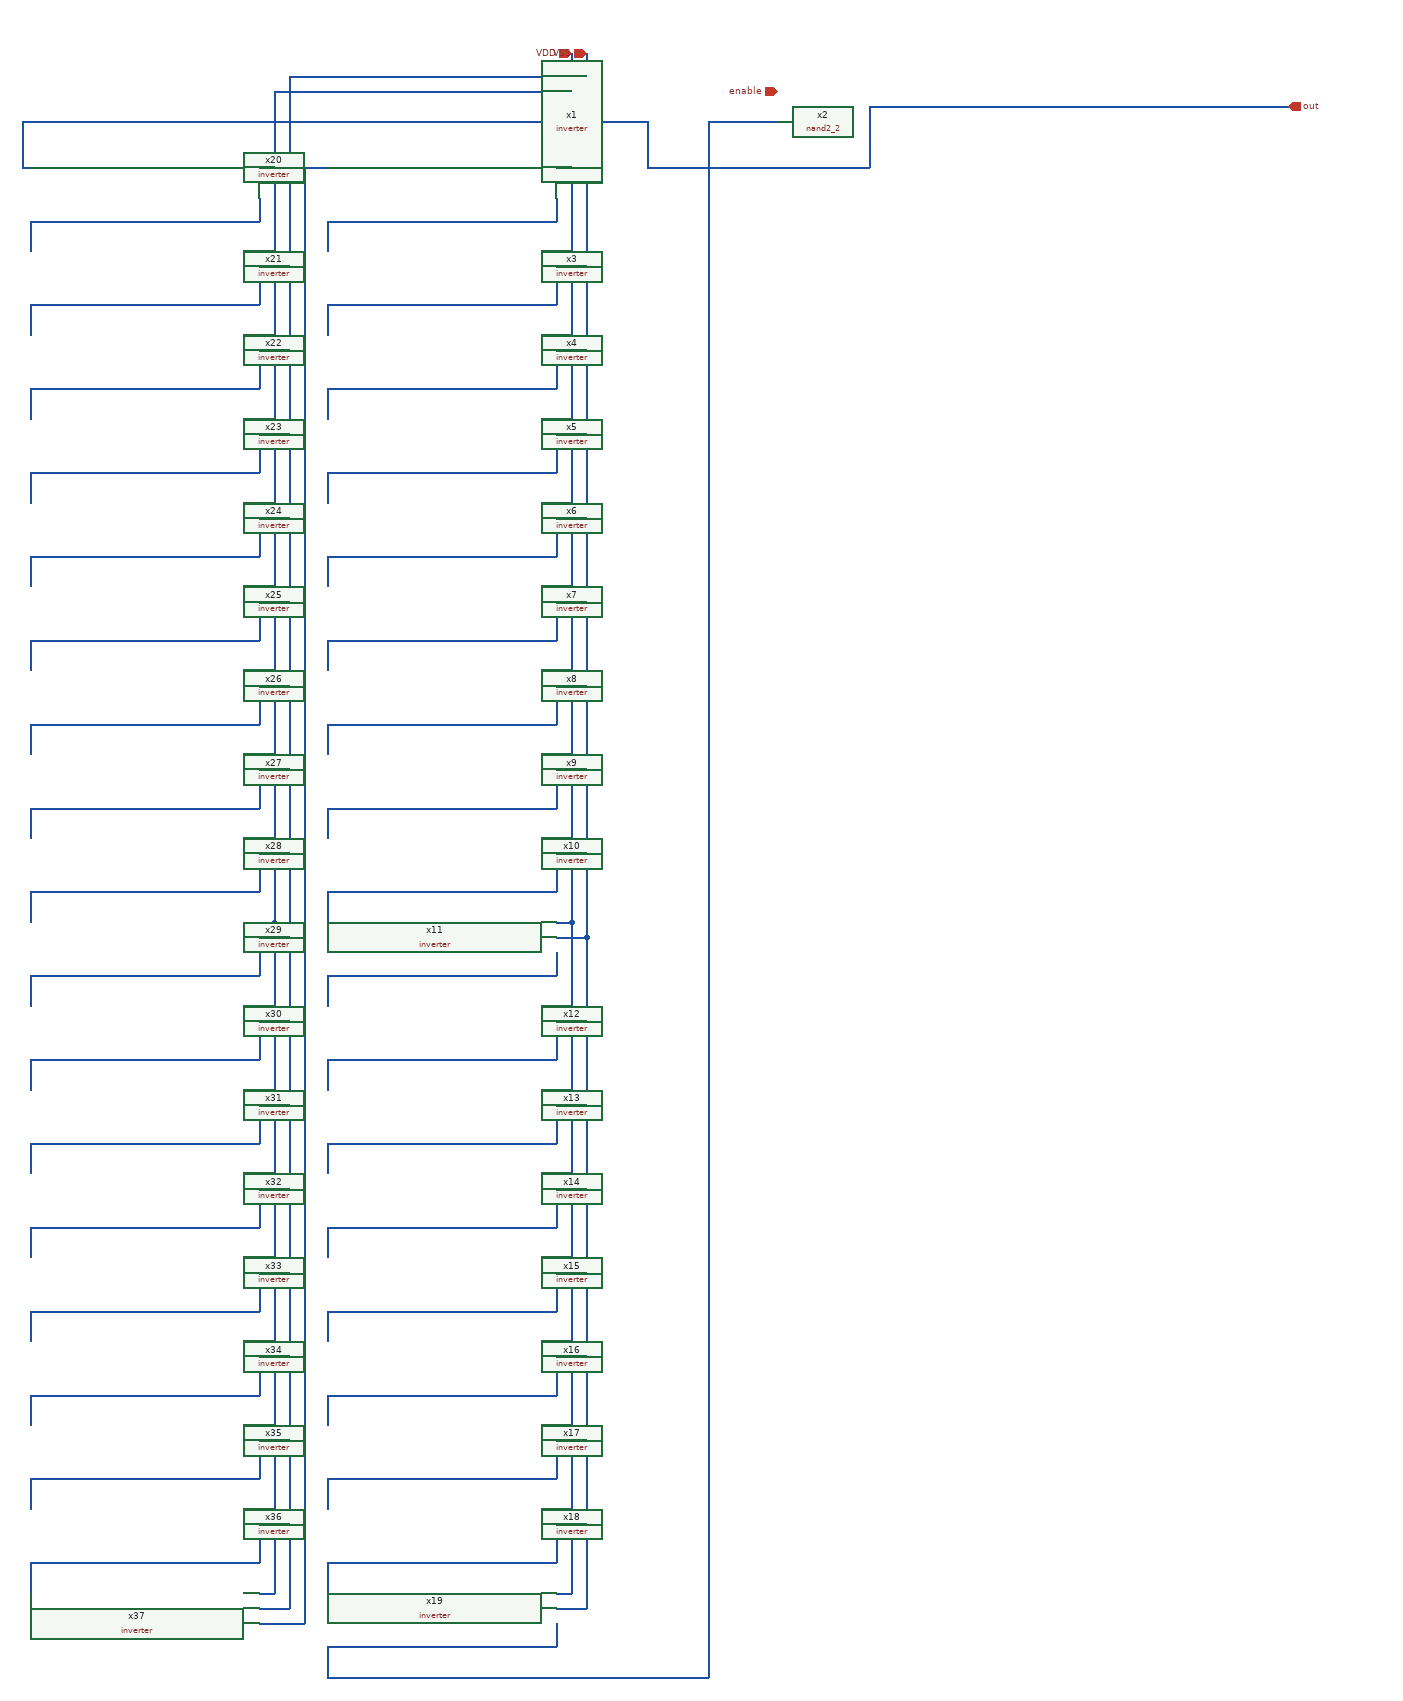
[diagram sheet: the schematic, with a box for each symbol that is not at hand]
v {xschem version=3.4.5 file_version=1.2
}
G {}
K {}
V {}
S {}
E {}
N -80 120 210 120 {
lab=pre_drive}
N -200 120 -180 120 {
lab=VDD}
N -200 140 -160 140 {
lab=VSS}
N -200 160 -200 190 {
lab=#net2}
N -500 190 -200 190 {
lab=#net2}
N -500 190 -500 230 {
lab=#net2}
N -200 230 -180 230 {
lab=VDD}
N -200 250 -160 250 {
lab=VSS}
N -200 270 -200 300 {
lab=#net3}
N -500 300 -200 300 {
lab=#net3}
N -500 300 -500 340 {
lab=#net3}
N -200 340 -180 340 {
lab=VDD}
N -200 360 -160 360 {
lab=VSS}
N -200 380 -200 410 {
lab=#net4}
N -500 410 -200 410 {
lab=#net4}
N -500 410 -500 450 {
lab=#net4}
N -200 450 -180 450 {
lab=VDD}
N -200 470 -160 470 {
lab=VSS}
N -200 490 -200 520 {
lab=#net5}
N -500 520 -200 520 {
lab=#net5}
N -500 520 -500 560 {
lab=#net5}
N -200 560 -180 560 {
lab=VDD}
N -200 580 -160 580 {
lab=VSS}
N -200 600 -200 630 {
lab=#net6}
N -500 630 -200 630 {
lab=#net6}
N -500 630 -500 670 {
lab=#net6}
N -200 670 -180 670 {
lab=VDD}
N -200 690 -160 690 {
lab=VSS}
N -200 710 -200 740 {
lab=#net7}
N -500 740 -200 740 {
lab=#net7}
N -500 740 -500 780 {
lab=#net7}
N -200 780 -180 780 {
lab=VDD}
N -200 800 -160 800 {
lab=VSS}
N -200 820 -200 850 {
lab=#net8}
N -500 850 -200 850 {
lab=#net8}
N -500 850 -500 890 {
lab=#net8}
N -200 890 -180 890 {
lab=VDD}
N -200 910 -160 910 {
lab=VSS}
N -200 930 -200 960 {
lab=#net9}
N -500 960 -200 960 {
lab=#net9}
N -500 960 -500 1000 {
lab=#net9}
N -200 1000 -180 1000 {
lab=VDD}
N -200 1020 -160 1020 {
lab=VSS}
N -200 1040 -200 1070 {
lab=#net10}
N -500 1070 -200 1070 {
lab=#net10}
N -500 1070 -500 1110 {
lab=#net10}
N -200 1110 -180 1110 {
lab=VDD}
N -200 1130 -160 1130 {
lab=VSS}
N -200 1150 -200 1180 {
lab=#net11}
N -500 1180 -200 1180 {
lab=#net11}
N -500 1180 -500 1220 {
lab=#net11}
N -160 -30 -160 1130 {
lab=VSS}
N -180 -30 -180 1110 {
lab=VDD}
N -200 1220 -180 1220 {
lab=VDD}
N -200 1240 -160 1240 {
lab=VSS}
N -200 1260 -200 1290 {
lab=#net12}
N -500 1290 -200 1290 {
lab=#net12}
N -500 1290 -500 1330 {
lab=#net12}
N -200 1330 -180 1330 {
lab=VDD}
N -200 1350 -160 1350 {
lab=VSS}
N -200 1370 -200 1400 {
lab=#net13}
N -500 1400 -200 1400 {
lab=#net13}
N -500 1400 -500 1440 {
lab=#net13}
N -200 1440 -180 1440 {
lab=VDD}
N -200 1460 -160 1460 {
lab=VSS}
N -200 1480 -200 1510 {
lab=#net14}
N -500 1510 -200 1510 {
lab=#net14}
N -500 1510 -500 1550 {
lab=#net14}
N -200 1550 -180 1550 {
lab=VDD}
N -200 1570 -160 1570 {
lab=VSS}
N -200 1590 -200 1620 {
lab=#net15}
N -500 1620 -200 1620 {
lab=#net15}
N -500 1620 -500 1660 {
lab=#net15}
N -200 1660 -180 1660 {
lab=VDD}
N -200 1680 -160 1680 {
lab=VSS}
N -200 1700 -200 1730 {
lab=#net16}
N -500 1730 -200 1730 {
lab=#net16}
N -500 1730 -500 1770 {
lab=#net16}
N -200 1770 -180 1770 {
lab=VDD}
N -200 1790 -160 1790 {
lab=VSS}
N -200 1810 -200 1840 {
lab=#net17}
N -500 1840 -200 1840 {
lab=#net17}
N -500 1840 -500 1880 {
lab=#net17}
N -200 1880 -180 1880 {
lab=VDD}
N -200 1900 -160 1900 {
lab=VSS}
N -200 1920 -200 1950 {
lab=#net18}
N -500 1950 -200 1950 {
lab=#net18}
N -500 1950 -500 1990 {
lab=#net18}
N -200 1990 -180 1990 {
lab=VDD}
N -200 2010 -160 2010 {
lab=VSS}
N -200 2030 -200 2060 {
lab=#net19}
N -500 2060 -200 2060 {
lab=#net19}
N -500 2060 -500 2100 {
lab=#net19}
N -180 1110 -180 1990 {
lab=VDD}
N -160 1130 -160 2010 {
lab=VSS}
N -500 2100 -0 2100 {
lab=#net19}
N 0 60 0 2100 {
lab=#net19}
N 0 60 90 60 {
lab=#net19}
N -80 60 -80 120 {
lab=pre_drive}
N -500 60 -80 60 {
lab=pre_drive}
N 660 40 760 40 {
lab=out}
N 210 40 210 120 {}
N 210 40 660 40 {}
N -590 120 -570 120 {
lab=VDD}
N -590 140 -550 140 {
lab=VSS}
N -590 160 -590 190 {
lab=#net2}
N -890 190 -590 190 {
lab=#net2}
N -890 190 -890 230 {
lab=#net2}
N -590 230 -570 230 {
lab=VDD}
N -590 250 -550 250 {
lab=VSS}
N -590 270 -590 300 {
lab=#net3}
N -890 300 -590 300 {
lab=#net3}
N -890 300 -890 340 {
lab=#net3}
N -590 340 -570 340 {
lab=VDD}
N -590 360 -550 360 {
lab=VSS}
N -590 380 -590 410 {
lab=#net4}
N -890 410 -590 410 {
lab=#net4}
N -890 410 -890 450 {
lab=#net4}
N -590 450 -570 450 {
lab=VDD}
N -590 470 -550 470 {
lab=VSS}
N -590 490 -590 520 {
lab=#net5}
N -890 520 -590 520 {
lab=#net5}
N -890 520 -890 560 {
lab=#net5}
N -590 560 -570 560 {
lab=VDD}
N -590 580 -550 580 {
lab=VSS}
N -590 600 -590 630 {
lab=#net6}
N -890 630 -590 630 {
lab=#net6}
N -890 630 -890 670 {
lab=#net6}
N -590 670 -570 670 {
lab=VDD}
N -590 690 -550 690 {
lab=VSS}
N -590 710 -590 740 {
lab=#net7}
N -890 740 -590 740 {
lab=#net7}
N -890 740 -890 780 {
lab=#net7}
N -590 780 -570 780 {
lab=VDD}
N -590 800 -550 800 {
lab=VSS}
N -590 820 -590 850 {
lab=#net8}
N -890 850 -590 850 {
lab=#net8}
N -890 850 -890 890 {
lab=#net8}
N -590 890 -570 890 {
lab=VDD}
N -590 910 -550 910 {
lab=VSS}
N -590 930 -590 960 {
lab=#net9}
N -890 960 -590 960 {
lab=#net9}
N -890 960 -890 1000 {
lab=#net9}
N -590 1000 -570 1000 {
lab=VDD}
N -590 1020 -550 1020 {
lab=VSS}
N -590 1040 -590 1070 {
lab=#net10}
N -890 1070 -590 1070 {
lab=#net10}
N -890 1070 -890 1110 {
lab=#net10}
N -590 1110 -570 1110 {
lab=VDD}
N -590 1130 -550 1130 {
lab=VSS}
N -590 1150 -590 1180 {
lab=#net11}
N -890 1180 -590 1180 {
lab=#net11}
N -890 1180 -890 1220 {
lab=#net11}
N -590 1220 -570 1220 {
lab=VDD}
N -590 1240 -550 1240 {
lab=VSS}
N -590 1260 -590 1290 {
lab=#net12}
N -890 1290 -590 1290 {
lab=#net12}
N -890 1290 -890 1330 {
lab=#net12}
N -590 1330 -570 1330 {
lab=VDD}
N -590 1350 -550 1350 {
lab=VSS}
N -590 1370 -590 1400 {
lab=#net13}
N -890 1400 -590 1400 {
lab=#net13}
N -890 1400 -890 1440 {
lab=#net13}
N -590 1440 -570 1440 {
lab=VDD}
N -590 1460 -550 1460 {
lab=VSS}
N -590 1480 -590 1510 {
lab=#net14}
N -890 1510 -590 1510 {
lab=#net14}
N -890 1510 -890 1550 {
lab=#net14}
N -590 1550 -570 1550 {
lab=VDD}
N -590 1570 -550 1570 {
lab=VSS}
N -590 1590 -590 1620 {
lab=#net15}
N -890 1620 -590 1620 {
lab=#net15}
N -890 1620 -890 1660 {
lab=#net15}
N -590 1660 -570 1660 {
lab=VDD}
N -590 1680 -550 1680 {
lab=VSS}
N -590 1700 -590 1730 {
lab=#net16}
N -890 1730 -590 1730 {
lab=#net16}
N -890 1730 -890 1770 {
lab=#net16}
N -590 1770 -570 1770 {
lab=VDD}
N -590 1790 -550 1790 {
lab=VSS}
N -590 1810 -590 1840 {
lab=#net17}
N -890 1840 -590 1840 {
lab=#net17}
N -890 1840 -890 1880 {
lab=#net17}
N -590 1880 -570 1880 {
lab=VDD}
N -590 1900 -550 1900 {
lab=VSS}
N -590 1920 -590 1950 {
lab=#net18}
N -890 1950 -590 1950 {
lab=#net18}
N -890 1950 -890 1990 {
lab=#net18}
N -590 1990 -570 1990 {
lab=VDD}
N -570 1110 -570 1990 {
lab=VDD}
N -590 2010 -550 2010 {}
N -550 0 -550 2010 {}
N -550 0 -160 0 {}
N -570 20 -180 20 {}
N -570 20 -570 1110 {}
N -900 60 -500 60 {}
N -900 60 -900 120 {}
N -900 120 -890 120 {}
N -590 2030 -530 2030 {}
N -530 120 -530 2030 {}
N -530 120 -500 120 {}
C {devices/iopin.sym} -180 -30 2 0 {name=p1 lab=VDD
}
C {devices/ipin.sym} 90 20 0 0 {name=p3 lab=enable}
C {sky130_stdcells/nand2_2.sym} 150 40 0 0 {name=x2 VGND=VSS VNB=VSS VPB=VDD VPWR=VDD prefix=sky130_fd_sc_hd__ }
C {inverter.sym} -350 140 0 0 {name=x1}
C {inverter.sym} -350 250 0 0 {name=x3}
C {inverter.sym} -350 360 0 0 {name=x4}
C {inverter.sym} -350 470 0 0 {name=x5}
C {inverter.sym} -350 580 0 0 {name=x6}
C {inverter.sym} -350 690 0 0 {name=x7}
C {inverter.sym} -350 800 0 0 {name=x8}
C {inverter.sym} -350 910 0 0 {name=x9}
C {inverter.sym} -350 1020 0 0 {name=x10}
C {inverter.sym} -350 1130 0 0 {name=x11}
C {devices/iopin.sym} -160 -30 0 0 {name=p2 lab=VSS
}
C {inverter.sym} -350 1240 0 0 {name=x12}
C {inverter.sym} -350 1350 0 0 {name=x13}
C {inverter.sym} -350 1460 0 0 {name=x14}
C {inverter.sym} -350 1570 0 0 {name=x15}
C {inverter.sym} -350 1680 0 0 {name=x16}
C {inverter.sym} -350 1790 0 0 {name=x17}
C {inverter.sym} -350 1900 0 0 {name=x18}
C {inverter.sym} -350 2010 0 0 {name=x19}
C {devices/opin.sym} 760 40 0 0 {name=p10 lab=out}
C {inverter.sym} -740 140 0 0 {name=x20}
C {inverter.sym} -740 250 0 0 {name=x21}
C {inverter.sym} -740 360 0 0 {name=x22}
C {inverter.sym} -740 470 0 0 {name=x23}
C {inverter.sym} -740 580 0 0 {name=x24}
C {inverter.sym} -740 690 0 0 {name=x25}
C {inverter.sym} -740 800 0 0 {name=x26}
C {inverter.sym} -740 910 0 0 {name=x27}
C {inverter.sym} -740 1020 0 0 {name=x28}
C {inverter.sym} -740 1130 0 0 {name=x29}
C {inverter.sym} -740 1240 0 0 {name=x30}
C {inverter.sym} -740 1350 0 0 {name=x31}
C {inverter.sym} -740 1460 0 0 {name=x32}
C {inverter.sym} -740 1570 0 0 {name=x33}
C {inverter.sym} -740 1680 0 0 {name=x34}
C {inverter.sym} -740 1790 0 0 {name=x35}
C {inverter.sym} -740 1900 0 0 {name=x36}
C {inverter.sym} -740 2010 0 0 {name=x37}
